VERSION 5.8 ;
BUSBITCHARS "[]" ;
DIVIDERCHAR "/" ;

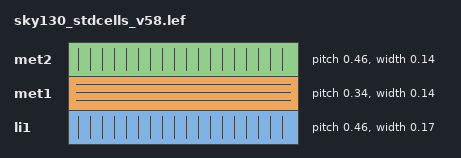
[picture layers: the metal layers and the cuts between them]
LAYER li1
  TYPE ROUTING ;
  DIRECTION VERTICAL ;
  PITCH 0.46 ;
  WIDTH 0.17 ;
END li1

LAYER met1
  TYPE ROUTING ;
  DIRECTION HORIZONTAL ;
  PITCH 0.34 ;
  WIDTH 0.14 ;
END met1

LAYER met2
  TYPE ROUTING ;
  DIRECTION VERTICAL ;
  PITCH 0.46 ;
  WIDTH 0.14 ;
END met2

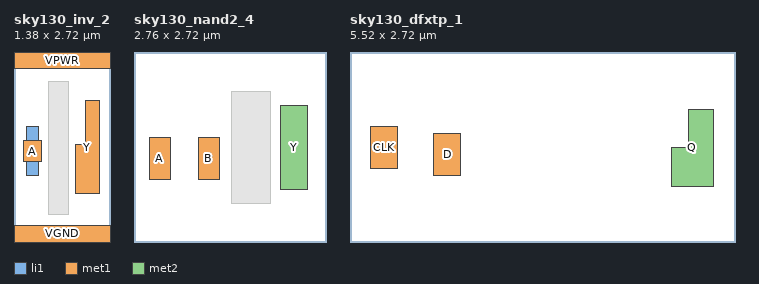
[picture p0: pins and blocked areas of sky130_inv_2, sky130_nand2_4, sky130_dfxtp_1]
MACRO sky130_inv_2
  CLASS CORE ;
  ORIGIN 0.00 0.00 ;
  SIZE 1.38 BY 2.72 ;
  SYMMETRY X Y ;
  PIN A
    DIRECTION INPUT ;
    USE SIGNAL ;
    PORT
      LAYER li1 ;
        RECT 0.18 0.95 0.35 1.65 ;
      LAYER met1 ;
        RECT 0.14 1.15 0.40 1.45 ;
    END
  END A
  PIN Y
    DIRECTION OUTPUT ;
    USE SIGNAL ;
    PORT
      LAYER met1 ;
        POLYGON 0.88 0.70 1.22 0.70 1.22 2.02 1.02 2.02 1.02 1.40 0.88 1.40 ;
    END
  END Y
  PIN VPWR
    DIRECTION INOUT ;
    USE POWER ;
    PORT
      LAYER met1 ;
        RECT 0.00 2.48 1.38 2.72 ;
    END
  END VPWR
  PIN VGND
    DIRECTION INOUT ;
    USE GROUND ;
    PORT
      LAYER met1 ;
        RECT 0.00 0.00 1.38 0.24 ;
    END
  END VGND
  OBS
    LAYER li1 ;
      RECT 0.50 0.40 0.78 2.30 ;
  END
END sky130_inv_2

MACRO sky130_nand2_4
  CLASS CORE ;
  ORIGIN 0.00 0.00 ;
  SIZE 2.76 BY 2.72 ;
  PIN A
    DIRECTION INPUT ;
    PORT
      LAYER met1 ;
        RECT 0.22 0.90 0.52 1.50 ;
    END
  END A
  PIN B
    DIRECTION INPUT ;
    PORT
      LAYER met1 ;
        RECT 0.92 0.90 1.22 1.50 ;
    END
  END B
  PIN Y
    DIRECTION OUTPUT ;
    PORT
      LAYER met2 ;
        RECT 2.10 0.75 2.48 1.95 ;
    END
  END Y
  OBS
    LAYER met1 ;
      RECT 1.40 0.55 1.95 2.15 ;
  END
END sky130_nand2_4

MACRO sky130_dfxtp_1
  CLASS CORE ;
  ORIGIN 0.00 0.00 ;
  SIZE 5.52 BY 2.72 ;
  PIN CLK
    DIRECTION INPUT ;
    USE CLOCK ;
    PORT
      LAYER met1 ;
        RECT 0.30 1.05 0.68 1.65 ;
    END
  END CLK
  PIN D
    DIRECTION INPUT ;
    PORT
      LAYER met1 ;
        RECT 1.20 0.95 1.58 1.55 ;
    END
  END D
  PIN Q
    DIRECTION OUTPUT ;
    PORT
      LAYER met2 ;
        POLYGON 4.60 0.80 5.20 0.80 5.20 1.90 4.85 1.90 4.85 1.35 4.60 1.35 ;
    END
  END Q
END sky130_dfxtp_1

END LIBRARY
